VERSION 5.7 ;
  NOWIREEXTENSIONATPIN ON ;
  DIVIDERCHAR "/" ;
  BUSBITCHARS "[]" ;
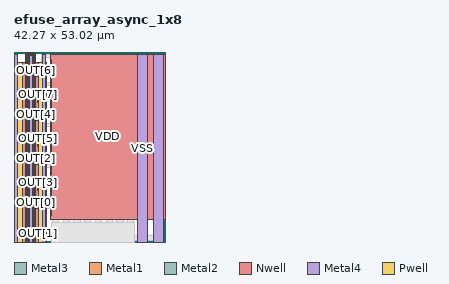
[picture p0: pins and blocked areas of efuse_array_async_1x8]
MACRO efuse_array_async_1x8
  CLASS BLOCK ;
  FOREIGN efuse_array_async_1x8 ;
  ORIGIN 0.000 0.000 ;
  SIZE 42.270 BY 53.020 ;
  PIN OUT[0]
    ANTENNADIFFAREA 0.897600 ;
    PORT
      LAYER Metal3 ;
        RECT 2.370 10.730 2.750 11.110 ;
    END
  END OUT[0]
  PIN OUT[1]
    ANTENNADIFFAREA 0.897600 ;
    PORT
      LAYER Metal3 ;
        RECT 6.490 2.070 6.970 2.550 ;
    END
  END OUT[1]
  PIN OUT[2]
    ANTENNADIFFAREA 0.897600 ;
    PORT
      LAYER Metal3 ;
        RECT 2.370 23.050 2.750 23.430 ;
    END
  END OUT[2]
  PIN OUT[3]
    ANTENNADIFFAREA 0.897600 ;
    PORT
      LAYER Metal3 ;
        RECT 6.490 14.390 6.970 14.870 ;
    END
  END OUT[3]
  PIN OUT[4]
    ANTENNADIFFAREA 0.897600 ;
    PORT
      LAYER Metal3 ;
        RECT 2.370 35.370 2.750 35.750 ;
    END
  END OUT[4]
  PIN OUT[5]
    ANTENNADIFFAREA 0.897600 ;
    PORT
      LAYER Metal3 ;
        RECT 6.490 26.710 6.970 27.190 ;
    END
  END OUT[5]
  PIN OUT[6]
    ANTENNADIFFAREA 0.897600 ;
    PORT
      LAYER Metal3 ;
        RECT 2.370 47.690 2.750 48.070 ;
    END
  END OUT[6]
  PIN OUT[7]
    ANTENNADIFFAREA 0.897600 ;
    PORT
      LAYER Metal3 ;
        RECT 6.490 39.030 6.970 39.510 ;
    END
  END OUT[7]
  PIN COL_PROG_N[0]
    ANTENNAGATEAREA 62.000000 ;
    PORT
      LAYER Metal1 ;
        RECT 10.130 7.380 10.430 10.940 ;
    END
  END COL_PROG_N[0]
  PIN COL_PROG_N[1]
    ANTENNAGATEAREA 62.000000 ;
    PORT
      LAYER Metal1 ;
        RECT 10.130 13.100 10.430 16.660 ;
    END
  END COL_PROG_N[1]
  PIN COL_PROG_N[2]
    ANTENNAGATEAREA 62.000000 ;
    PORT
      LAYER Metal1 ;
        RECT 10.130 18.820 10.430 22.380 ;
    END
  END COL_PROG_N[2]
  PIN COL_PROG_N[3]
    ANTENNAGATEAREA 62.000000 ;
    PORT
      LAYER Metal1 ;
        RECT 10.130 24.540 10.430 28.100 ;
    END
  END COL_PROG_N[3]
  PIN COL_PROG_N[4]
    ANTENNAGATEAREA 62.000000 ;
    PORT
      LAYER Metal1 ;
        RECT 10.130 30.260 10.430 33.820 ;
    END
  END COL_PROG_N[4]
  PIN COL_PROG_N[5]
    ANTENNAGATEAREA 62.000000 ;
    PORT
      LAYER Metal1 ;
        RECT 10.130 35.980 10.430 39.540 ;
    END
  END COL_PROG_N[5]
  PIN COL_PROG_N[6]
    ANTENNAGATEAREA 62.000000 ;
    PORT
      LAYER Metal1 ;
        RECT 10.130 41.700 10.430 45.260 ;
    END
  END COL_PROG_N[6]
  PIN COL_PROG_N[7]
    ANTENNAGATEAREA 62.000000 ;
    PORT
      LAYER Metal1 ;
        RECT 10.130 47.420 10.430 50.980 ;
    END
  END COL_PROG_N[7]
  PIN PRESET_N
    ANTENNAGATEAREA 9.760000 ;
    PORT
      LAYER Metal2 ;
        RECT 3.760 52.180 5.480 52.460 ;
        RECT 3.760 39.595 4.040 52.180 ;
        RECT 3.680 39.215 4.040 39.595 ;
        RECT 3.760 27.275 4.040 39.215 ;
        RECT 3.680 26.895 4.040 27.275 ;
        RECT 3.760 14.955 4.040 26.895 ;
        RECT 3.680 14.575 4.040 14.955 ;
        RECT 3.760 2.635 4.040 14.575 ;
        RECT 3.680 2.255 4.040 2.635 ;
        RECT 3.760 0.000 4.040 2.255 ;
        RECT 5.200 47.885 5.480 52.180 ;
        RECT 5.200 47.505 5.560 47.885 ;
        RECT 5.200 35.565 5.480 47.505 ;
        RECT 5.200 35.185 5.560 35.565 ;
        RECT 5.200 23.245 5.480 35.185 ;
        RECT 5.200 22.865 5.560 23.245 ;
        RECT 5.200 10.925 5.480 22.865 ;
        RECT 5.200 10.545 5.560 10.925 ;
        RECT 5.200 0.000 5.480 10.545 ;
    END
  END PRESET_N
  PIN SENSE
    ANTENNAGATEAREA 3.936000 ;
    PORT
      LAYER Metal2 ;
        RECT 3.115 52.740 6.125 53.020 ;
        RECT 3.115 40.780 3.395 52.740 ;
        RECT 1.970 40.400 3.395 40.780 ;
        RECT 3.115 28.460 3.395 40.400 ;
        RECT 1.970 28.080 3.395 28.460 ;
        RECT 3.115 16.140 3.395 28.080 ;
        RECT 1.970 15.760 3.395 16.140 ;
        RECT 3.115 3.820 3.395 15.760 ;
        RECT 1.970 3.440 3.395 3.820 ;
        RECT 3.115 0.000 3.395 3.440 ;
        RECT 5.845 46.700 6.125 52.740 ;
        RECT 5.845 46.320 7.270 46.700 ;
        RECT 5.845 34.380 6.125 46.320 ;
        RECT 5.845 34.000 7.270 34.380 ;
        RECT 5.845 22.060 6.125 34.000 ;
        RECT 5.845 21.680 7.270 22.060 ;
        RECT 5.845 9.740 6.125 21.680 ;
        RECT 5.845 9.360 7.270 9.740 ;
        RECT 5.845 0.000 6.125 9.360 ;
    END
  END SENSE
  PIN VDD
    USE POWER ;
    PORT
      LAYER Nwell ;
        RECT 2.460 0.000 6.780 50.140 ;
      LAYER Metal4 ;
        RECT 4.260 0.000 5.260 52.460 ;
    END
    PORT
      LAYER Nwell ;
        RECT 10.070 6.340 42.270 52.380 ;
      LAYER Metal4 ;
        RECT 38.820 0.000 41.680 52.460 ;
    END
  END VDD
  PIN VSS
    USE GROUND ;
    PORT
      LAYER Metal4 ;
        RECT 34.510 0.000 37.370 52.460 ;
    END
    PORT
      LAYER Pwell ;
        RECT 6.780 0.000 8.970 50.140 ;
      LAYER Metal4 ;
        RECT 7.900 0.000 8.900 52.460 ;
    END
    PORT
      LAYER Pwell ;
        RECT 0.270 0.000 2.460 50.140 ;
      LAYER Metal4 ;
        RECT 0.000 0.000 1.000 52.460 ;
    END
  END VSS
  OBS
      LAYER Metal1 ;
        RECT 0.400 49.320 1.000 52.460 ;
        RECT 4.320 49.320 4.920 52.460 ;
        RECT 8.240 49.320 8.840 52.460 ;
        RECT 10.670 51.780 41.670 52.220 ;
        RECT 38.885 51.720 39.265 51.780 ;
        RECT 39.625 51.720 40.005 51.780 ;
        RECT 40.365 51.720 40.745 51.780 ;
        RECT 41.105 51.720 41.485 51.780 ;
        RECT 10.660 51.050 41.680 51.430 ;
        RECT 10.660 50.030 41.680 50.400 ;
        RECT 38.890 49.970 39.270 50.030 ;
        RECT 39.630 49.970 40.010 50.030 ;
        RECT 40.370 49.970 40.750 50.030 ;
        RECT 41.110 49.970 41.490 50.030 ;
        RECT 0.400 48.980 1.885 49.320 ;
        RECT 2.630 48.980 6.610 49.320 ;
        RECT 7.355 48.980 8.840 49.320 ;
        RECT 10.660 49.010 41.680 49.380 ;
        RECT 0.400 46.825 1.000 48.980 ;
        RECT 4.320 48.345 4.920 48.980 ;
        RECT 4.320 48.115 5.900 48.345 ;
        RECT 2.370 47.945 2.750 48.070 ;
        RECT 1.230 47.615 4.090 47.945 ;
        RECT 1.900 47.060 2.900 47.385 ;
        RECT 4.320 46.925 4.920 48.115 ;
        RECT 6.330 47.885 6.690 47.970 ;
        RECT 5.200 47.655 6.690 47.885 ;
        RECT 5.200 47.505 5.560 47.655 ;
        RECT 0.400 46.595 1.860 46.825 ;
        RECT 3.230 46.695 4.920 46.925 ;
        RECT 5.150 46.870 6.100 47.275 ;
        RECT 0.400 44.585 1.000 46.595 ;
        RECT 4.320 46.075 4.920 46.695 ;
        RECT 4.320 45.845 5.610 46.075 ;
        RECT 1.230 45.375 4.090 45.705 ;
        RECT 1.900 44.820 2.900 45.145 ;
        RECT 4.320 44.885 4.920 45.845 ;
        RECT 5.840 45.525 6.100 46.870 ;
        RECT 6.330 46.220 6.690 47.655 ;
        RECT 6.920 46.320 7.270 47.520 ;
        RECT 7.630 46.910 8.010 48.555 ;
        RECT 6.710 45.525 7.060 45.585 ;
        RECT 7.630 45.525 7.970 46.130 ;
        RECT 5.840 45.265 7.970 45.525 ;
        RECT 6.710 45.205 7.060 45.265 ;
        RECT 8.240 44.985 8.840 48.980 ;
        RECT 31.770 48.950 33.390 49.010 ;
        RECT 10.660 47.990 41.680 48.360 ;
        RECT 38.890 47.930 39.270 47.990 ;
        RECT 39.630 47.930 40.010 47.990 ;
        RECT 40.370 47.930 40.750 47.990 ;
        RECT 41.110 47.930 41.490 47.990 ;
        RECT 10.660 46.970 41.680 47.340 ;
        RECT 31.770 46.910 33.390 46.970 ;
        RECT 10.670 46.060 41.670 46.500 ;
        RECT 38.885 46.000 39.265 46.060 ;
        RECT 39.625 46.000 40.005 46.060 ;
        RECT 40.365 46.000 40.745 46.060 ;
        RECT 41.105 46.000 41.485 46.060 ;
        RECT 10.660 45.330 41.680 45.710 ;
        RECT 0.400 44.355 1.860 44.585 ;
        RECT 0.400 42.345 1.000 44.355 ;
        RECT 2.250 43.465 2.515 44.820 ;
        RECT 4.320 44.685 6.010 44.885 ;
        RECT 7.380 44.755 8.840 44.985 ;
        RECT 3.230 44.655 6.010 44.685 ;
        RECT 3.230 44.455 4.920 44.655 ;
        RECT 1.230 43.135 4.090 43.465 ;
        RECT 1.900 42.580 2.900 42.905 ;
        RECT 4.320 42.645 4.920 44.455 ;
        RECT 6.340 44.195 7.340 44.520 ;
        RECT 5.150 43.635 8.010 43.965 ;
        RECT 4.320 42.445 6.010 42.645 ;
        RECT 3.230 42.415 6.010 42.445 ;
        RECT 0.400 42.115 1.860 42.345 ;
        RECT 3.230 42.215 4.920 42.415 ;
        RECT 6.725 42.280 6.990 43.635 ;
        RECT 8.240 42.745 8.840 44.755 ;
        RECT 10.660 44.310 41.680 44.680 ;
        RECT 38.890 44.250 39.270 44.310 ;
        RECT 39.630 44.250 40.010 44.310 ;
        RECT 40.370 44.250 40.750 44.310 ;
        RECT 41.110 44.250 41.490 44.310 ;
        RECT 10.660 43.290 41.680 43.660 ;
        RECT 28.770 43.230 30.390 43.290 ;
        RECT 7.380 42.515 8.840 42.745 ;
        RECT 0.400 38.120 1.000 42.115 ;
        RECT 2.180 41.835 2.530 41.895 ;
        RECT 1.270 41.575 3.400 41.835 ;
        RECT 1.270 40.970 1.610 41.575 ;
        RECT 2.180 41.515 2.530 41.575 ;
        RECT 1.230 38.545 1.610 40.190 ;
        RECT 1.970 39.580 2.320 40.780 ;
        RECT 2.550 39.445 2.910 40.880 ;
        RECT 3.140 40.230 3.400 41.575 ;
        RECT 4.320 41.255 4.920 42.215 ;
        RECT 6.340 41.955 7.340 42.280 ;
        RECT 5.150 41.395 8.010 41.725 ;
        RECT 3.630 41.025 4.920 41.255 ;
        RECT 4.320 40.405 4.920 41.025 ;
        RECT 8.240 40.505 8.840 42.515 ;
        RECT 10.660 42.270 41.680 42.640 ;
        RECT 38.890 42.210 39.270 42.270 ;
        RECT 39.630 42.210 40.010 42.270 ;
        RECT 40.370 42.210 40.750 42.270 ;
        RECT 41.110 42.210 41.490 42.270 ;
        RECT 10.660 41.250 41.680 41.620 ;
        RECT 28.770 41.190 30.390 41.250 ;
        RECT 3.140 39.825 4.090 40.230 ;
        RECT 4.320 40.175 6.010 40.405 ;
        RECT 7.380 40.275 8.840 40.505 ;
        RECT 10.670 40.340 41.670 40.780 ;
        RECT 38.885 40.280 39.265 40.340 ;
        RECT 39.625 40.280 40.005 40.340 ;
        RECT 40.365 40.280 40.745 40.340 ;
        RECT 41.105 40.280 41.485 40.340 ;
        RECT 3.680 39.445 4.040 39.595 ;
        RECT 2.550 39.215 4.040 39.445 ;
        RECT 2.550 39.130 2.910 39.215 ;
        RECT 4.320 38.985 4.920 40.175 ;
        RECT 6.340 39.715 7.340 40.040 ;
        RECT 5.150 39.155 8.010 39.485 ;
        RECT 6.490 39.030 6.870 39.155 ;
        RECT 3.340 38.755 4.920 38.985 ;
        RECT 4.320 38.120 4.920 38.755 ;
        RECT 8.240 38.120 8.840 40.275 ;
        RECT 10.660 39.610 41.680 39.990 ;
        RECT 10.660 38.590 41.680 38.960 ;
        RECT 38.890 38.530 39.270 38.590 ;
        RECT 39.630 38.530 40.010 38.590 ;
        RECT 40.370 38.530 40.750 38.590 ;
        RECT 41.110 38.530 41.490 38.590 ;
        RECT 0.400 37.780 1.885 38.120 ;
        RECT 2.630 37.780 6.610 38.120 ;
        RECT 7.355 37.780 8.840 38.120 ;
        RECT 0.400 37.000 1.000 37.780 ;
        RECT 4.320 37.000 4.920 37.780 ;
        RECT 8.240 37.000 8.840 37.780 ;
        RECT 10.660 37.570 41.680 37.940 ;
        RECT 25.770 37.510 27.390 37.570 ;
        RECT 0.400 36.660 1.885 37.000 ;
        RECT 2.630 36.660 6.610 37.000 ;
        RECT 7.355 36.660 8.840 37.000 ;
        RECT 0.400 34.505 1.000 36.660 ;
        RECT 4.320 36.025 4.920 36.660 ;
        RECT 4.320 35.795 5.900 36.025 ;
        RECT 2.370 35.625 2.750 35.750 ;
        RECT 1.230 35.295 4.090 35.625 ;
        RECT 1.900 34.740 2.900 35.065 ;
        RECT 4.320 34.605 4.920 35.795 ;
        RECT 6.330 35.565 6.690 35.650 ;
        RECT 5.200 35.335 6.690 35.565 ;
        RECT 5.200 35.185 5.560 35.335 ;
        RECT 0.400 34.275 1.860 34.505 ;
        RECT 3.230 34.375 4.920 34.605 ;
        RECT 5.150 34.550 6.100 34.955 ;
        RECT 0.400 32.265 1.000 34.275 ;
        RECT 4.320 33.755 4.920 34.375 ;
        RECT 4.320 33.525 5.610 33.755 ;
        RECT 1.230 33.055 4.090 33.385 ;
        RECT 1.900 32.500 2.900 32.825 ;
        RECT 4.320 32.565 4.920 33.525 ;
        RECT 5.840 33.205 6.100 34.550 ;
        RECT 6.330 33.900 6.690 35.335 ;
        RECT 6.920 34.000 7.270 35.200 ;
        RECT 7.630 34.590 8.010 36.235 ;
        RECT 6.710 33.205 7.060 33.265 ;
        RECT 7.630 33.205 7.970 33.810 ;
        RECT 5.840 32.945 7.970 33.205 ;
        RECT 6.710 32.885 7.060 32.945 ;
        RECT 8.240 32.665 8.840 36.660 ;
        RECT 10.660 36.550 41.680 36.920 ;
        RECT 38.890 36.490 39.270 36.550 ;
        RECT 39.630 36.490 40.010 36.550 ;
        RECT 40.370 36.490 40.750 36.550 ;
        RECT 41.110 36.490 41.490 36.550 ;
        RECT 10.660 35.530 41.680 35.900 ;
        RECT 25.770 35.470 27.390 35.530 ;
        RECT 10.670 34.620 41.670 35.060 ;
        RECT 38.885 34.560 39.265 34.620 ;
        RECT 39.625 34.560 40.005 34.620 ;
        RECT 40.365 34.560 40.745 34.620 ;
        RECT 41.105 34.560 41.485 34.620 ;
        RECT 10.660 33.890 41.680 34.270 ;
        RECT 10.660 32.870 41.680 33.240 ;
        RECT 38.890 32.810 39.270 32.870 ;
        RECT 39.630 32.810 40.010 32.870 ;
        RECT 40.370 32.810 40.750 32.870 ;
        RECT 41.110 32.810 41.490 32.870 ;
        RECT 0.400 32.035 1.860 32.265 ;
        RECT 0.400 30.025 1.000 32.035 ;
        RECT 2.250 31.145 2.515 32.500 ;
        RECT 4.320 32.365 6.010 32.565 ;
        RECT 7.380 32.435 8.840 32.665 ;
        RECT 3.230 32.335 6.010 32.365 ;
        RECT 3.230 32.135 4.920 32.335 ;
        RECT 1.230 30.815 4.090 31.145 ;
        RECT 1.900 30.260 2.900 30.585 ;
        RECT 4.320 30.325 4.920 32.135 ;
        RECT 6.340 31.875 7.340 32.200 ;
        RECT 5.150 31.315 8.010 31.645 ;
        RECT 4.320 30.125 6.010 30.325 ;
        RECT 3.230 30.095 6.010 30.125 ;
        RECT 0.400 29.795 1.860 30.025 ;
        RECT 3.230 29.895 4.920 30.095 ;
        RECT 6.725 29.960 6.990 31.315 ;
        RECT 8.240 30.425 8.840 32.435 ;
        RECT 10.660 31.850 41.680 32.220 ;
        RECT 22.770 31.790 24.390 31.850 ;
        RECT 10.660 30.830 41.680 31.200 ;
        RECT 38.890 30.770 39.270 30.830 ;
        RECT 39.630 30.770 40.010 30.830 ;
        RECT 40.370 30.770 40.750 30.830 ;
        RECT 41.110 30.770 41.490 30.830 ;
        RECT 7.380 30.195 8.840 30.425 ;
        RECT 0.400 25.800 1.000 29.795 ;
        RECT 2.180 29.515 2.530 29.575 ;
        RECT 1.270 29.255 3.400 29.515 ;
        RECT 1.270 28.650 1.610 29.255 ;
        RECT 2.180 29.195 2.530 29.255 ;
        RECT 1.230 26.225 1.610 27.870 ;
        RECT 1.970 27.260 2.320 28.460 ;
        RECT 2.550 27.125 2.910 28.560 ;
        RECT 3.140 27.910 3.400 29.255 ;
        RECT 4.320 28.935 4.920 29.895 ;
        RECT 6.340 29.635 7.340 29.960 ;
        RECT 5.150 29.075 8.010 29.405 ;
        RECT 3.630 28.705 4.920 28.935 ;
        RECT 4.320 28.085 4.920 28.705 ;
        RECT 8.240 28.185 8.840 30.195 ;
        RECT 10.660 29.810 41.680 30.180 ;
        RECT 22.770 29.750 24.390 29.810 ;
        RECT 10.670 28.900 41.670 29.340 ;
        RECT 38.885 28.840 39.265 28.900 ;
        RECT 39.625 28.840 40.005 28.900 ;
        RECT 40.365 28.840 40.745 28.900 ;
        RECT 41.105 28.840 41.485 28.900 ;
        RECT 3.140 27.505 4.090 27.910 ;
        RECT 4.320 27.855 6.010 28.085 ;
        RECT 7.380 27.955 8.840 28.185 ;
        RECT 10.660 28.170 41.680 28.550 ;
        RECT 3.680 27.125 4.040 27.275 ;
        RECT 2.550 26.895 4.040 27.125 ;
        RECT 2.550 26.810 2.910 26.895 ;
        RECT 4.320 26.665 4.920 27.855 ;
        RECT 6.340 27.395 7.340 27.720 ;
        RECT 5.150 26.835 8.010 27.165 ;
        RECT 6.490 26.710 6.870 26.835 ;
        RECT 3.340 26.435 4.920 26.665 ;
        RECT 4.320 25.800 4.920 26.435 ;
        RECT 8.240 25.800 8.840 27.955 ;
        RECT 10.660 27.150 41.680 27.520 ;
        RECT 38.890 27.090 39.270 27.150 ;
        RECT 39.630 27.090 40.010 27.150 ;
        RECT 40.370 27.090 40.750 27.150 ;
        RECT 41.110 27.090 41.490 27.150 ;
        RECT 10.660 26.130 41.680 26.500 ;
        RECT 19.770 26.070 21.390 26.130 ;
        RECT 0.400 25.460 1.885 25.800 ;
        RECT 2.630 25.460 6.610 25.800 ;
        RECT 7.355 25.460 8.840 25.800 ;
        RECT 0.400 24.680 1.000 25.460 ;
        RECT 4.320 24.680 4.920 25.460 ;
        RECT 8.240 24.680 8.840 25.460 ;
        RECT 10.660 25.110 41.680 25.480 ;
        RECT 38.890 25.050 39.270 25.110 ;
        RECT 39.630 25.050 40.010 25.110 ;
        RECT 40.370 25.050 40.750 25.110 ;
        RECT 41.110 25.050 41.490 25.110 ;
        RECT 0.400 24.340 1.885 24.680 ;
        RECT 2.630 24.340 6.610 24.680 ;
        RECT 7.355 24.340 8.840 24.680 ;
        RECT 0.400 22.185 1.000 24.340 ;
        RECT 4.320 23.705 4.920 24.340 ;
        RECT 4.320 23.475 5.900 23.705 ;
        RECT 2.370 23.305 2.750 23.430 ;
        RECT 1.230 22.975 4.090 23.305 ;
        RECT 1.900 22.420 2.900 22.745 ;
        RECT 4.320 22.285 4.920 23.475 ;
        RECT 6.330 23.245 6.690 23.330 ;
        RECT 5.200 23.015 6.690 23.245 ;
        RECT 5.200 22.865 5.560 23.015 ;
        RECT 0.400 21.955 1.860 22.185 ;
        RECT 3.230 22.055 4.920 22.285 ;
        RECT 5.150 22.230 6.100 22.635 ;
        RECT 0.400 19.945 1.000 21.955 ;
        RECT 4.320 21.435 4.920 22.055 ;
        RECT 4.320 21.205 5.610 21.435 ;
        RECT 1.230 20.735 4.090 21.065 ;
        RECT 1.900 20.180 2.900 20.505 ;
        RECT 4.320 20.245 4.920 21.205 ;
        RECT 5.840 20.885 6.100 22.230 ;
        RECT 6.330 21.580 6.690 23.015 ;
        RECT 6.920 21.680 7.270 22.880 ;
        RECT 7.630 22.270 8.010 23.915 ;
        RECT 6.710 20.885 7.060 20.945 ;
        RECT 7.630 20.885 7.970 21.490 ;
        RECT 5.840 20.625 7.970 20.885 ;
        RECT 6.710 20.565 7.060 20.625 ;
        RECT 8.240 20.345 8.840 24.340 ;
        RECT 10.660 24.090 41.680 24.460 ;
        RECT 19.770 24.030 21.390 24.090 ;
        RECT 10.670 23.180 41.670 23.620 ;
        RECT 38.885 23.120 39.265 23.180 ;
        RECT 39.625 23.120 40.005 23.180 ;
        RECT 40.365 23.120 40.745 23.180 ;
        RECT 41.105 23.120 41.485 23.180 ;
        RECT 10.660 22.450 41.680 22.830 ;
        RECT 10.660 21.430 41.680 21.800 ;
        RECT 38.890 21.370 39.270 21.430 ;
        RECT 39.630 21.370 40.010 21.430 ;
        RECT 40.370 21.370 40.750 21.430 ;
        RECT 41.110 21.370 41.490 21.430 ;
        RECT 10.660 20.410 41.680 20.780 ;
        RECT 16.770 20.350 18.390 20.410 ;
        RECT 0.400 19.715 1.860 19.945 ;
        RECT 0.400 17.705 1.000 19.715 ;
        RECT 2.250 18.825 2.515 20.180 ;
        RECT 4.320 20.045 6.010 20.245 ;
        RECT 7.380 20.115 8.840 20.345 ;
        RECT 3.230 20.015 6.010 20.045 ;
        RECT 3.230 19.815 4.920 20.015 ;
        RECT 1.230 18.495 4.090 18.825 ;
        RECT 1.900 17.940 2.900 18.265 ;
        RECT 4.320 18.005 4.920 19.815 ;
        RECT 6.340 19.555 7.340 19.880 ;
        RECT 5.150 18.995 8.010 19.325 ;
        RECT 4.320 17.805 6.010 18.005 ;
        RECT 3.230 17.775 6.010 17.805 ;
        RECT 0.400 17.475 1.860 17.705 ;
        RECT 3.230 17.575 4.920 17.775 ;
        RECT 6.725 17.640 6.990 18.995 ;
        RECT 8.240 18.105 8.840 20.115 ;
        RECT 10.660 19.390 41.680 19.760 ;
        RECT 38.890 19.330 39.270 19.390 ;
        RECT 39.630 19.330 40.010 19.390 ;
        RECT 40.370 19.330 40.750 19.390 ;
        RECT 41.110 19.330 41.490 19.390 ;
        RECT 10.660 18.370 41.680 18.740 ;
        RECT 16.770 18.310 18.390 18.370 ;
        RECT 7.380 17.875 8.840 18.105 ;
        RECT 0.400 13.480 1.000 17.475 ;
        RECT 2.180 17.195 2.530 17.255 ;
        RECT 1.270 16.935 3.400 17.195 ;
        RECT 1.270 16.330 1.610 16.935 ;
        RECT 2.180 16.875 2.530 16.935 ;
        RECT 1.230 13.905 1.610 15.550 ;
        RECT 1.970 14.940 2.320 16.140 ;
        RECT 2.550 14.805 2.910 16.240 ;
        RECT 3.140 15.590 3.400 16.935 ;
        RECT 4.320 16.615 4.920 17.575 ;
        RECT 6.340 17.315 7.340 17.640 ;
        RECT 5.150 16.755 8.010 17.085 ;
        RECT 3.630 16.385 4.920 16.615 ;
        RECT 4.320 15.765 4.920 16.385 ;
        RECT 8.240 15.865 8.840 17.875 ;
        RECT 10.670 17.460 41.670 17.900 ;
        RECT 38.885 17.400 39.265 17.460 ;
        RECT 39.625 17.400 40.005 17.460 ;
        RECT 40.365 17.400 40.745 17.460 ;
        RECT 41.105 17.400 41.485 17.460 ;
        RECT 10.660 16.730 41.680 17.110 ;
        RECT 3.140 15.185 4.090 15.590 ;
        RECT 4.320 15.535 6.010 15.765 ;
        RECT 7.380 15.635 8.840 15.865 ;
        RECT 10.660 15.710 41.680 16.080 ;
        RECT 38.890 15.650 39.270 15.710 ;
        RECT 39.630 15.650 40.010 15.710 ;
        RECT 40.370 15.650 40.750 15.710 ;
        RECT 41.110 15.650 41.490 15.710 ;
        RECT 3.680 14.805 4.040 14.955 ;
        RECT 2.550 14.575 4.040 14.805 ;
        RECT 2.550 14.490 2.910 14.575 ;
        RECT 4.320 14.345 4.920 15.535 ;
        RECT 6.340 15.075 7.340 15.400 ;
        RECT 5.150 14.515 8.010 14.845 ;
        RECT 6.490 14.390 6.870 14.515 ;
        RECT 3.340 14.115 4.920 14.345 ;
        RECT 4.320 13.480 4.920 14.115 ;
        RECT 8.240 13.480 8.840 15.635 ;
        RECT 10.660 14.690 41.680 15.060 ;
        RECT 13.770 14.630 15.390 14.690 ;
        RECT 10.660 13.670 41.680 14.040 ;
        RECT 38.890 13.610 39.270 13.670 ;
        RECT 39.630 13.610 40.010 13.670 ;
        RECT 40.370 13.610 40.750 13.670 ;
        RECT 41.110 13.610 41.490 13.670 ;
        RECT 0.400 13.140 1.885 13.480 ;
        RECT 2.630 13.140 6.610 13.480 ;
        RECT 7.355 13.140 8.840 13.480 ;
        RECT 0.400 12.360 1.000 13.140 ;
        RECT 4.320 12.360 4.920 13.140 ;
        RECT 8.240 12.360 8.840 13.140 ;
        RECT 10.660 12.650 41.680 13.020 ;
        RECT 13.770 12.590 15.390 12.650 ;
        RECT 0.400 12.020 1.885 12.360 ;
        RECT 2.630 12.020 6.610 12.360 ;
        RECT 7.355 12.020 8.840 12.360 ;
        RECT 0.400 9.865 1.000 12.020 ;
        RECT 4.320 11.385 4.920 12.020 ;
        RECT 4.320 11.155 5.900 11.385 ;
        RECT 2.370 10.985 2.750 11.110 ;
        RECT 1.230 10.655 4.090 10.985 ;
        RECT 1.900 10.100 2.900 10.425 ;
        RECT 4.320 9.965 4.920 11.155 ;
        RECT 6.330 10.925 6.690 11.010 ;
        RECT 5.200 10.695 6.690 10.925 ;
        RECT 5.200 10.545 5.560 10.695 ;
        RECT 0.400 9.635 1.860 9.865 ;
        RECT 3.230 9.735 4.920 9.965 ;
        RECT 5.150 9.910 6.100 10.315 ;
        RECT 0.400 7.625 1.000 9.635 ;
        RECT 4.320 9.115 4.920 9.735 ;
        RECT 4.320 8.885 5.610 9.115 ;
        RECT 1.230 8.415 4.090 8.745 ;
        RECT 1.900 7.860 2.900 8.185 ;
        RECT 4.320 7.925 4.920 8.885 ;
        RECT 5.840 8.565 6.100 9.910 ;
        RECT 6.330 9.260 6.690 10.695 ;
        RECT 6.920 9.360 7.270 10.560 ;
        RECT 7.630 9.950 8.010 11.595 ;
        RECT 6.710 8.565 7.060 8.625 ;
        RECT 7.630 8.565 7.970 9.170 ;
        RECT 5.840 8.305 7.970 8.565 ;
        RECT 6.710 8.245 7.060 8.305 ;
        RECT 8.240 8.025 8.840 12.020 ;
        RECT 10.670 11.740 41.670 12.180 ;
        RECT 38.885 11.680 39.265 11.740 ;
        RECT 39.625 11.680 40.005 11.740 ;
        RECT 40.365 11.680 40.745 11.740 ;
        RECT 41.105 11.680 41.485 11.740 ;
        RECT 10.660 11.010 41.680 11.390 ;
        RECT 10.660 9.990 41.680 10.360 ;
        RECT 38.890 9.930 39.270 9.990 ;
        RECT 39.630 9.930 40.010 9.990 ;
        RECT 40.370 9.930 40.750 9.990 ;
        RECT 41.110 9.930 41.490 9.990 ;
        RECT 10.660 8.970 41.680 9.340 ;
        RECT 10.770 8.910 12.390 8.970 ;
        RECT 0.400 7.395 1.860 7.625 ;
        RECT 0.400 5.385 1.000 7.395 ;
        RECT 2.250 6.505 2.515 7.860 ;
        RECT 4.320 7.725 6.010 7.925 ;
        RECT 7.380 7.795 8.840 8.025 ;
        RECT 10.660 7.950 41.680 8.320 ;
        RECT 38.890 7.890 39.270 7.950 ;
        RECT 39.630 7.890 40.010 7.950 ;
        RECT 40.370 7.890 40.750 7.950 ;
        RECT 41.110 7.890 41.490 7.950 ;
        RECT 3.230 7.695 6.010 7.725 ;
        RECT 3.230 7.495 4.920 7.695 ;
        RECT 1.230 6.175 4.090 6.505 ;
        RECT 1.900 5.620 2.900 5.945 ;
        RECT 4.320 5.685 4.920 7.495 ;
        RECT 6.340 7.235 7.340 7.560 ;
        RECT 5.150 6.675 8.010 7.005 ;
        RECT 4.320 5.485 6.010 5.685 ;
        RECT 3.230 5.455 6.010 5.485 ;
        RECT 0.400 5.155 1.860 5.385 ;
        RECT 3.230 5.255 4.920 5.455 ;
        RECT 6.725 5.320 6.990 6.675 ;
        RECT 8.240 5.785 8.840 7.795 ;
        RECT 10.660 6.930 41.680 7.300 ;
        RECT 10.770 6.870 12.390 6.930 ;
        RECT 7.380 5.555 8.840 5.785 ;
        RECT 0.400 1.160 1.000 5.155 ;
        RECT 2.180 4.875 2.530 4.935 ;
        RECT 1.270 4.615 3.400 4.875 ;
        RECT 1.270 4.010 1.610 4.615 ;
        RECT 2.180 4.555 2.530 4.615 ;
        RECT 1.230 1.585 1.610 3.230 ;
        RECT 1.970 2.620 2.320 3.820 ;
        RECT 2.550 2.485 2.910 3.920 ;
        RECT 3.140 3.270 3.400 4.615 ;
        RECT 4.320 4.295 4.920 5.255 ;
        RECT 6.340 4.995 7.340 5.320 ;
        RECT 5.150 4.435 8.010 4.765 ;
        RECT 3.630 4.065 4.920 4.295 ;
        RECT 4.320 3.445 4.920 4.065 ;
        RECT 8.240 3.545 8.840 5.555 ;
        RECT 10.705 4.195 12.455 6.080 ;
        RECT 13.705 4.195 15.455 6.080 ;
        RECT 16.705 4.195 18.455 6.080 ;
        RECT 19.705 4.195 21.455 6.080 ;
        RECT 22.705 4.195 24.455 6.080 ;
        RECT 25.705 4.195 27.455 6.080 ;
        RECT 28.705 4.195 30.455 6.080 ;
        RECT 31.705 4.195 33.455 6.080 ;
        RECT 3.140 2.865 4.090 3.270 ;
        RECT 4.320 3.215 6.010 3.445 ;
        RECT 7.380 3.315 8.840 3.545 ;
        RECT 3.680 2.485 4.040 2.635 ;
        RECT 2.550 2.255 4.040 2.485 ;
        RECT 2.550 2.170 2.910 2.255 ;
        RECT 4.320 2.025 4.920 3.215 ;
        RECT 6.340 2.755 7.340 3.080 ;
        RECT 5.150 2.195 8.010 2.525 ;
        RECT 6.490 2.070 6.870 2.195 ;
        RECT 3.340 1.795 4.920 2.025 ;
        RECT 4.320 1.160 4.920 1.795 ;
        RECT 8.240 1.160 8.840 3.315 ;
        RECT 11.175 3.195 11.985 4.195 ;
        RECT 14.175 3.195 14.985 4.195 ;
        RECT 17.175 3.195 17.985 4.195 ;
        RECT 20.175 3.195 20.985 4.195 ;
        RECT 23.175 3.195 23.985 4.195 ;
        RECT 26.175 3.195 26.985 4.195 ;
        RECT 29.175 3.195 29.985 4.195 ;
        RECT 32.175 3.195 32.985 4.195 ;
        RECT 11.490 1.840 32.670 3.100 ;
        RECT 0.400 0.820 1.885 1.160 ;
        RECT 2.630 0.820 6.610 1.160 ;
        RECT 7.355 0.820 8.840 1.160 ;
        RECT 0.400 0.000 1.000 0.820 ;
        RECT 4.320 0.000 4.920 0.820 ;
        RECT 8.240 0.000 8.840 0.820 ;
        RECT 10.705 0.405 41.680 1.745 ;
      LAYER Metal2 ;
        RECT 0.510 48.850 0.890 49.230 ;
        RECT 4.370 48.850 4.750 49.230 ;
        RECT 2.370 47.690 2.750 48.070 ;
        RECT 7.630 47.965 8.010 48.345 ;
        RECT 1.550 47.060 2.305 47.385 ;
        RECT 0.510 45.850 0.890 46.230 ;
        RECT 0.510 42.850 0.890 43.230 ;
        RECT 1.550 43.145 1.900 47.060 ;
        RECT 4.370 45.850 4.750 46.230 ;
        RECT 8.350 45.850 8.730 46.230 ;
        RECT 2.180 41.515 2.530 45.705 ;
        RECT 4.370 42.850 4.750 43.230 ;
        RECT 6.710 41.395 7.060 45.585 ;
        RECT 0.510 39.850 0.890 40.230 ;
        RECT 1.230 39.600 1.610 39.980 ;
        RECT 4.370 39.850 4.750 40.230 ;
        RECT 7.340 40.040 7.690 43.955 ;
        RECT 8.350 42.850 8.730 43.230 ;
        RECT 6.935 39.715 7.690 40.040 ;
        RECT 6.490 39.030 6.870 39.410 ;
        RECT 0.510 36.850 0.890 37.230 ;
        RECT 4.370 36.850 4.750 37.230 ;
        RECT 2.370 35.370 2.750 35.750 ;
        RECT 7.630 35.645 8.010 36.025 ;
        RECT 1.550 34.740 2.305 35.065 ;
        RECT 0.510 33.850 0.890 34.230 ;
        RECT 0.510 30.850 0.890 31.230 ;
        RECT 1.550 30.825 1.900 34.740 ;
        RECT 4.370 33.850 4.750 34.230 ;
        RECT 8.350 33.850 8.730 34.230 ;
        RECT 2.180 29.195 2.530 33.385 ;
        RECT 4.370 30.850 4.750 31.230 ;
        RECT 6.710 29.075 7.060 33.265 ;
        RECT 0.510 27.850 0.890 28.230 ;
        RECT 4.370 27.850 4.750 28.230 ;
        RECT 7.340 27.720 7.690 31.635 ;
        RECT 8.350 30.850 8.730 31.230 ;
        RECT 1.230 27.280 1.610 27.660 ;
        RECT 6.935 27.395 7.690 27.720 ;
        RECT 6.490 26.710 6.870 27.090 ;
        RECT 0.510 24.850 0.890 25.230 ;
        RECT 4.370 24.850 4.750 25.230 ;
        RECT 2.370 23.050 2.750 23.430 ;
        RECT 7.630 23.325 8.010 23.705 ;
        RECT 1.550 22.420 2.305 22.745 ;
        RECT 0.510 21.850 0.890 22.230 ;
        RECT 0.510 18.850 0.890 19.230 ;
        RECT 1.550 18.505 1.900 22.420 ;
        RECT 2.180 16.875 2.530 21.065 ;
        RECT 4.370 18.850 4.750 19.230 ;
        RECT 6.710 16.755 7.060 20.945 ;
        RECT 0.510 15.850 0.890 16.230 ;
        RECT 4.370 15.850 4.750 16.230 ;
        RECT 7.340 15.400 7.690 19.315 ;
        RECT 8.350 18.850 8.730 19.230 ;
        RECT 1.230 14.960 1.610 15.340 ;
        RECT 6.935 15.075 7.690 15.400 ;
        RECT 6.490 14.390 6.870 14.770 ;
        RECT 0.510 12.850 0.890 13.230 ;
        RECT 4.370 12.850 4.750 13.230 ;
        RECT 2.370 10.730 2.750 11.110 ;
        RECT 7.630 11.005 8.010 11.385 ;
        RECT 0.510 9.850 0.890 10.230 ;
        RECT 1.550 10.100 2.305 10.425 ;
        RECT 0.510 6.850 0.890 7.230 ;
        RECT 1.550 6.185 1.900 10.100 ;
        RECT 2.180 4.555 2.530 8.745 ;
        RECT 4.370 6.850 4.750 7.230 ;
        RECT 6.710 4.435 7.060 8.625 ;
        RECT 0.510 3.850 0.890 4.230 ;
        RECT 4.370 3.850 4.750 4.230 ;
        RECT 7.340 3.080 7.690 6.995 ;
        RECT 8.350 6.850 8.730 7.230 ;
        RECT 10.705 4.980 12.455 12.180 ;
        RECT 13.705 4.980 15.455 17.900 ;
        RECT 16.705 4.980 18.455 23.620 ;
        RECT 19.705 4.980 21.455 29.340 ;
        RECT 22.705 4.980 24.455 35.060 ;
        RECT 25.705 4.980 27.455 40.780 ;
        RECT 28.705 4.980 30.455 46.500 ;
        RECT 31.705 4.980 33.455 52.220 ;
        RECT 38.885 51.720 39.265 52.100 ;
        RECT 39.625 51.720 40.005 52.100 ;
        RECT 40.365 51.720 40.745 52.100 ;
        RECT 41.105 51.720 41.485 52.100 ;
        RECT 38.890 49.970 39.270 50.350 ;
        RECT 39.630 49.970 40.010 50.350 ;
        RECT 40.370 49.970 40.750 50.350 ;
        RECT 41.110 49.970 41.490 50.350 ;
        RECT 38.890 47.930 39.270 48.310 ;
        RECT 39.630 47.930 40.010 48.310 ;
        RECT 40.370 47.930 40.750 48.310 ;
        RECT 41.110 47.930 41.490 48.310 ;
        RECT 38.885 46.000 39.265 46.380 ;
        RECT 39.625 46.000 40.005 46.380 ;
        RECT 40.365 46.000 40.745 46.380 ;
        RECT 41.105 46.000 41.485 46.380 ;
        RECT 38.890 44.250 39.270 44.630 ;
        RECT 39.630 44.250 40.010 44.630 ;
        RECT 40.370 44.250 40.750 44.630 ;
        RECT 41.110 44.250 41.490 44.630 ;
        RECT 38.890 42.210 39.270 42.590 ;
        RECT 39.630 42.210 40.010 42.590 ;
        RECT 40.370 42.210 40.750 42.590 ;
        RECT 41.110 42.210 41.490 42.590 ;
        RECT 38.885 40.280 39.265 40.660 ;
        RECT 39.625 40.280 40.005 40.660 ;
        RECT 40.365 40.280 40.745 40.660 ;
        RECT 41.105 40.280 41.485 40.660 ;
        RECT 38.890 38.530 39.270 38.910 ;
        RECT 39.630 38.530 40.010 38.910 ;
        RECT 40.370 38.530 40.750 38.910 ;
        RECT 41.110 38.530 41.490 38.910 ;
        RECT 38.890 36.490 39.270 36.870 ;
        RECT 39.630 36.490 40.010 36.870 ;
        RECT 40.370 36.490 40.750 36.870 ;
        RECT 41.110 36.490 41.490 36.870 ;
        RECT 38.885 34.560 39.265 34.940 ;
        RECT 39.625 34.560 40.005 34.940 ;
        RECT 40.365 34.560 40.745 34.940 ;
        RECT 41.105 34.560 41.485 34.940 ;
        RECT 38.890 32.810 39.270 33.190 ;
        RECT 39.630 32.810 40.010 33.190 ;
        RECT 40.370 32.810 40.750 33.190 ;
        RECT 41.110 32.810 41.490 33.190 ;
        RECT 38.890 30.770 39.270 31.150 ;
        RECT 39.630 30.770 40.010 31.150 ;
        RECT 40.370 30.770 40.750 31.150 ;
        RECT 41.110 30.770 41.490 31.150 ;
        RECT 38.885 28.840 39.265 29.220 ;
        RECT 39.625 28.840 40.005 29.220 ;
        RECT 40.365 28.840 40.745 29.220 ;
        RECT 41.105 28.840 41.485 29.220 ;
        RECT 38.890 27.090 39.270 27.470 ;
        RECT 39.630 27.090 40.010 27.470 ;
        RECT 40.370 27.090 40.750 27.470 ;
        RECT 41.110 27.090 41.490 27.470 ;
        RECT 38.890 25.050 39.270 25.430 ;
        RECT 39.630 25.050 40.010 25.430 ;
        RECT 40.370 25.050 40.750 25.430 ;
        RECT 41.110 25.050 41.490 25.430 ;
        RECT 38.885 23.120 39.265 23.500 ;
        RECT 39.625 23.120 40.005 23.500 ;
        RECT 40.365 23.120 40.745 23.500 ;
        RECT 41.105 23.120 41.485 23.500 ;
        RECT 38.890 21.370 39.270 21.750 ;
        RECT 39.630 21.370 40.010 21.750 ;
        RECT 40.370 21.370 40.750 21.750 ;
        RECT 41.110 21.370 41.490 21.750 ;
        RECT 38.890 19.330 39.270 19.710 ;
        RECT 39.630 19.330 40.010 19.710 ;
        RECT 40.370 19.330 40.750 19.710 ;
        RECT 41.110 19.330 41.490 19.710 ;
        RECT 38.885 17.400 39.265 17.780 ;
        RECT 39.625 17.400 40.005 17.780 ;
        RECT 40.365 17.400 40.745 17.780 ;
        RECT 41.105 17.400 41.485 17.780 ;
        RECT 38.890 15.650 39.270 16.030 ;
        RECT 39.630 15.650 40.010 16.030 ;
        RECT 40.370 15.650 40.750 16.030 ;
        RECT 41.110 15.650 41.490 16.030 ;
        RECT 38.890 13.610 39.270 13.990 ;
        RECT 39.630 13.610 40.010 13.990 ;
        RECT 40.370 13.610 40.750 13.990 ;
        RECT 41.110 13.610 41.490 13.990 ;
        RECT 38.885 11.680 39.265 12.060 ;
        RECT 39.625 11.680 40.005 12.060 ;
        RECT 40.365 11.680 40.745 12.060 ;
        RECT 41.105 11.680 41.485 12.060 ;
        RECT 38.890 9.930 39.270 10.310 ;
        RECT 39.630 9.930 40.010 10.310 ;
        RECT 40.370 9.930 40.750 10.310 ;
        RECT 41.110 9.930 41.490 10.310 ;
        RECT 38.890 7.890 39.270 8.270 ;
        RECT 39.630 7.890 40.010 8.270 ;
        RECT 40.370 7.890 40.750 8.270 ;
        RECT 41.110 7.890 41.490 8.270 ;
        RECT 8.350 3.850 8.730 4.230 ;
        RECT 1.230 2.640 1.610 3.020 ;
        RECT 6.935 2.755 7.690 3.080 ;
        RECT 6.490 2.070 6.870 2.450 ;
        RECT 11.490 1.840 32.670 3.100 ;
        RECT 0.510 0.850 0.890 1.230 ;
        RECT 4.370 0.850 4.750 1.230 ;
        RECT 8.350 0.850 8.730 1.230 ;
        RECT 10.705 0.405 41.680 1.745 ;
      LAYER Metal3 ;
        RECT 7.630 51.420 33.455 52.220 ;
        RECT 38.885 51.720 39.265 52.100 ;
        RECT 39.625 51.720 40.005 52.100 ;
        RECT 40.365 51.720 40.745 52.100 ;
        RECT 41.105 51.720 41.485 52.100 ;
        RECT 0.510 48.850 0.890 49.230 ;
        RECT 4.370 48.850 4.750 49.230 ;
        RECT 7.630 47.755 8.430 51.420 ;
        RECT 38.890 49.970 39.270 50.350 ;
        RECT 39.630 49.970 40.010 50.350 ;
        RECT 40.370 49.970 40.750 50.350 ;
        RECT 41.110 49.970 41.490 50.350 ;
        RECT 38.890 47.930 39.270 48.310 ;
        RECT 39.630 47.930 40.010 48.310 ;
        RECT 40.370 47.930 40.750 48.310 ;
        RECT 41.110 47.930 41.490 48.310 ;
        RECT 0.510 45.850 0.890 46.230 ;
        RECT 4.370 45.850 4.750 46.230 ;
        RECT 8.350 45.850 8.730 46.230 ;
        RECT 38.885 46.000 39.265 46.380 ;
        RECT 39.625 46.000 40.005 46.380 ;
        RECT 40.365 46.000 40.745 46.380 ;
        RECT 41.105 46.000 41.485 46.380 ;
        RECT 1.230 43.700 30.455 44.500 ;
        RECT 38.890 44.250 39.270 44.630 ;
        RECT 39.630 44.250 40.010 44.630 ;
        RECT 40.370 44.250 40.750 44.630 ;
        RECT 41.110 44.250 41.490 44.630 ;
        RECT 0.510 42.850 0.890 43.230 ;
        RECT 0.510 39.850 0.890 40.230 ;
        RECT 1.230 39.390 2.030 43.700 ;
        RECT 4.370 42.850 4.750 43.230 ;
        RECT 8.350 42.850 8.730 43.230 ;
        RECT 38.890 42.210 39.270 42.590 ;
        RECT 39.630 42.210 40.010 42.590 ;
        RECT 40.370 42.210 40.750 42.590 ;
        RECT 41.110 42.210 41.490 42.590 ;
        RECT 4.370 39.850 4.750 40.230 ;
        RECT 7.630 39.980 27.455 40.780 ;
        RECT 38.885 40.280 39.265 40.660 ;
        RECT 39.625 40.280 40.005 40.660 ;
        RECT 40.365 40.280 40.745 40.660 ;
        RECT 41.105 40.280 41.485 40.660 ;
        RECT 0.510 36.850 0.890 37.230 ;
        RECT 4.370 36.850 4.750 37.230 ;
        RECT 7.630 35.435 8.430 39.980 ;
        RECT 38.890 38.530 39.270 38.910 ;
        RECT 39.630 38.530 40.010 38.910 ;
        RECT 40.370 38.530 40.750 38.910 ;
        RECT 41.110 38.530 41.490 38.910 ;
        RECT 38.890 36.490 39.270 36.870 ;
        RECT 39.630 36.490 40.010 36.870 ;
        RECT 40.370 36.490 40.750 36.870 ;
        RECT 41.110 36.490 41.490 36.870 ;
        RECT 38.885 34.560 39.265 34.940 ;
        RECT 39.625 34.560 40.005 34.940 ;
        RECT 40.365 34.560 40.745 34.940 ;
        RECT 41.105 34.560 41.485 34.940 ;
        RECT 0.510 33.850 0.890 34.230 ;
        RECT 4.370 33.850 4.750 34.230 ;
        RECT 8.350 33.850 8.730 34.230 ;
        RECT 1.230 32.260 24.455 33.060 ;
        RECT 38.890 32.810 39.270 33.190 ;
        RECT 39.630 32.810 40.010 33.190 ;
        RECT 40.370 32.810 40.750 33.190 ;
        RECT 41.110 32.810 41.490 33.190 ;
        RECT 0.510 30.850 0.890 31.230 ;
        RECT 0.510 27.850 0.890 28.230 ;
        RECT 1.230 27.070 2.030 32.260 ;
        RECT 4.370 30.850 4.750 31.230 ;
        RECT 8.350 30.850 8.730 31.230 ;
        RECT 38.890 30.770 39.270 31.150 ;
        RECT 39.630 30.770 40.010 31.150 ;
        RECT 40.370 30.770 40.750 31.150 ;
        RECT 41.110 30.770 41.490 31.150 ;
        RECT 7.630 28.540 21.455 29.340 ;
        RECT 38.885 28.840 39.265 29.220 ;
        RECT 39.625 28.840 40.005 29.220 ;
        RECT 40.365 28.840 40.745 29.220 ;
        RECT 41.105 28.840 41.485 29.220 ;
        RECT 4.370 27.850 4.750 28.230 ;
        RECT 0.510 24.850 0.890 25.230 ;
        RECT 4.370 24.850 4.750 25.230 ;
        RECT 7.630 23.115 8.430 28.540 ;
        RECT 38.890 27.090 39.270 27.470 ;
        RECT 39.630 27.090 40.010 27.470 ;
        RECT 40.370 27.090 40.750 27.470 ;
        RECT 41.110 27.090 41.490 27.470 ;
        RECT 38.890 25.050 39.270 25.430 ;
        RECT 39.630 25.050 40.010 25.430 ;
        RECT 40.370 25.050 40.750 25.430 ;
        RECT 41.110 25.050 41.490 25.430 ;
        RECT 38.885 23.120 39.265 23.500 ;
        RECT 39.625 23.120 40.005 23.500 ;
        RECT 40.365 23.120 40.745 23.500 ;
        RECT 41.105 23.120 41.485 23.500 ;
        RECT 0.510 21.850 0.890 22.230 ;
        RECT 1.230 20.820 18.455 21.620 ;
        RECT 38.890 21.370 39.270 21.750 ;
        RECT 39.630 21.370 40.010 21.750 ;
        RECT 40.370 21.370 40.750 21.750 ;
        RECT 41.110 21.370 41.490 21.750 ;
        RECT 0.510 18.850 0.890 19.230 ;
        RECT 0.510 15.850 0.890 16.230 ;
        RECT 1.230 14.750 2.030 20.820 ;
        RECT 38.890 19.330 39.270 19.710 ;
        RECT 39.630 19.330 40.010 19.710 ;
        RECT 40.370 19.330 40.750 19.710 ;
        RECT 41.110 19.330 41.490 19.710 ;
        RECT 4.370 18.850 4.750 19.230 ;
        RECT 8.350 18.850 8.730 19.230 ;
        RECT 7.630 17.100 15.455 17.900 ;
        RECT 38.885 17.400 39.265 17.780 ;
        RECT 39.625 17.400 40.005 17.780 ;
        RECT 40.365 17.400 40.745 17.780 ;
        RECT 41.105 17.400 41.485 17.780 ;
        RECT 4.370 15.850 4.750 16.230 ;
        RECT 0.510 12.850 0.890 13.230 ;
        RECT 4.370 12.850 4.750 13.230 ;
        RECT 7.630 10.795 8.430 17.100 ;
        RECT 38.890 15.650 39.270 16.030 ;
        RECT 39.630 15.650 40.010 16.030 ;
        RECT 40.370 15.650 40.750 16.030 ;
        RECT 41.110 15.650 41.490 16.030 ;
        RECT 38.890 13.610 39.270 13.990 ;
        RECT 39.630 13.610 40.010 13.990 ;
        RECT 40.370 13.610 40.750 13.990 ;
        RECT 41.110 13.610 41.490 13.990 ;
        RECT 38.885 11.680 39.265 12.060 ;
        RECT 39.625 11.680 40.005 12.060 ;
        RECT 40.365 11.680 40.745 12.060 ;
        RECT 41.105 11.680 41.485 12.060 ;
        RECT 0.510 9.850 0.890 10.230 ;
        RECT 1.230 9.380 12.455 10.180 ;
        RECT 38.890 9.930 39.270 10.310 ;
        RECT 39.630 9.930 40.010 10.310 ;
        RECT 40.370 9.930 40.750 10.310 ;
        RECT 41.110 9.930 41.490 10.310 ;
        RECT 0.510 6.850 0.890 7.230 ;
        RECT 0.510 3.850 0.890 4.230 ;
        RECT 1.230 2.430 2.030 9.380 ;
        RECT 38.890 7.890 39.270 8.270 ;
        RECT 39.630 7.890 40.010 8.270 ;
        RECT 40.370 7.890 40.750 8.270 ;
        RECT 41.110 7.890 41.490 8.270 ;
        RECT 4.370 6.850 4.750 7.230 ;
        RECT 8.350 6.850 8.730 7.230 ;
        RECT 4.370 3.850 4.750 4.230 ;
        RECT 8.350 3.850 8.730 4.230 ;
        RECT 0.510 0.850 0.890 1.230 ;
        RECT 4.370 0.850 4.750 1.230 ;
        RECT 8.350 0.850 8.730 1.230 ;
        RECT 10.450 0.000 33.710 5.530 ;
        RECT 34.510 0.575 37.370 1.575 ;
      LAYER Metal4 ;
        RECT 10.450 0.000 33.710 5.530 ;
      LAYER Metal5 ;
        RECT 10.450 0.000 33.710 5.530 ;
  END
END efuse_array_async_1x8
END LIBRARY

